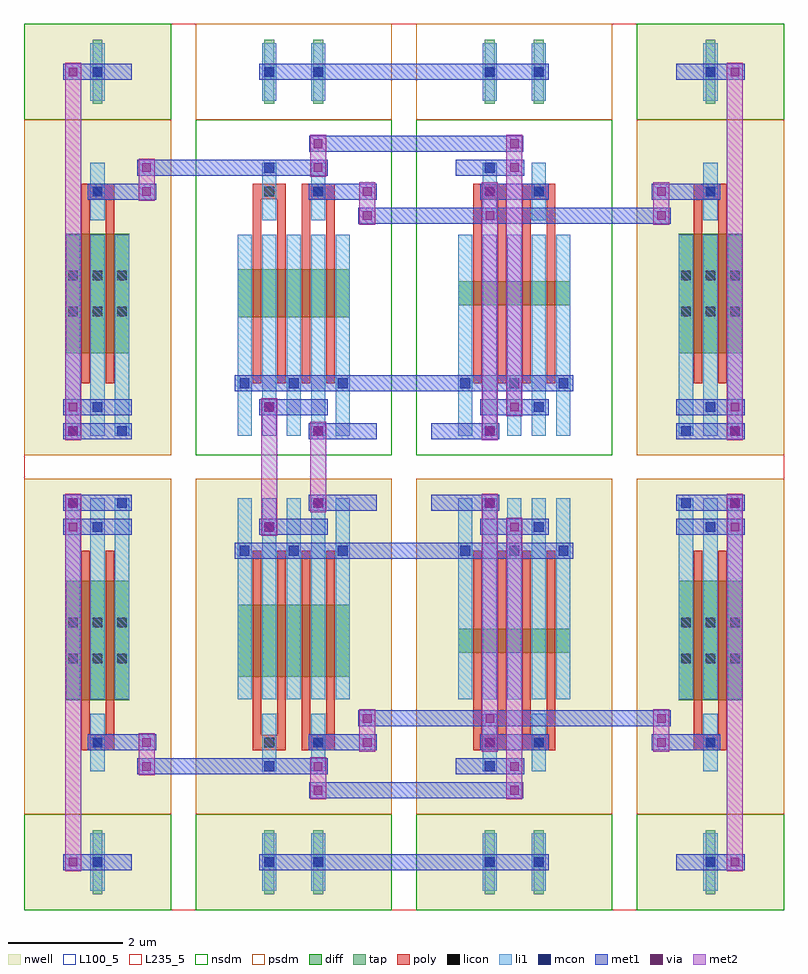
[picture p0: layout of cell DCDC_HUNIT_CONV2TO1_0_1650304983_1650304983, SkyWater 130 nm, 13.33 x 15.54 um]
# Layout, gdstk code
from math import pi, radians
import gdstk
lib = gdstk.Library(unit=1e-6, precision=1e-09)
def R(c, l, rs):  # rectangles x0, y0, x1, y1
    for r in rs: c.add(gdstk.rectangle(r[:2], r[2:], *l))
def A(c, l, x, y, w, h, nx, ny, dx, dy):  # array of equal rectangles
    R(c, l, [(x+i*dx, y+j*dy, x+i*dx+w, y+j*dy+h) for i in range(nx) for j in range(ny)])
def P(c, l, *ps):  # polygons
    for p in ps: c.add(gdstk.Polygon(p, *l))
nwell = (64, 20)
diff = (65, 20)
tap = (65, 44)
poly = (66, 20)
licon = (66, 44)
li1 = (67, 20)
mcon = (67, 44)
met1 = (68, 20)
via = (68, 44)
met2 = (69, 20)
nsdm = (93, 44)
psdm = (94, 20)
L100_5 = (100, 5)
L235_5 = (235, 5)

ccp_pmos_b_88242555_x1_y = lib.new_cell('CCP_PMOS_B_88242555_X1_Y1_1650304983_1650304984_1650304983_1650304983')
R(ccp_pmos_b_88242555_x1_y, nwell, [(0,0,3.44,7.56)])
R(ccp_pmos_b_88242555_x1_y, diff, [(0.735,2.625,2.705,3.045)])
R(ccp_pmos_b_88242555_x1_y, tap, [(1.205,6.16,1.375,7.28), (2.065,6.16,2.235,7.28)])
A(ccp_pmos_b_88242555_x1_y, poly, 1, 1.26, 0.15, 3.36, 4, 1, 0.43, 0)
R(ccp_pmos_b_88242555_x1_y, poly, [(1,4.485,1.58,4.755), (1.86,4.485,2.44,4.755)])
R(ccp_pmos_b_88242555_x1_y, licon, [(1.205,4.535,1.375,4.705), (2.065,4.535,2.235,4.705), (1.205,6.635,1.375,6.805), (2.065,6.635,2.235,6.805)])
A(ccp_pmos_b_88242555_x1_y, li1, 0.735, 0.335, 0.25, 3.53, 5, 1, 0.43, 0)
R(ccp_pmos_b_88242555_x1_y, li1, [(1.165,4.115,1.415,5.125), (2.025,4.115,2.275,5.125), (1.165,6.215,1.415,7.225), (2.025,6.215,2.275,7.225)])
A(ccp_pmos_b_88242555_x1_y, mcon, 0.775, 1.175, 0.17, 0.17, 3, 1, 0.86, 0)
R(ccp_pmos_b_88242555_x1_y, mcon, [(1.205,0.335,1.375,0.505), (2.065,0.755,2.235,0.925), (2.065,4.535,2.235,4.705), (1.205,4.955,1.375,5.125), (1.205,6.635,1.375,6.805), (2.065,6.635,2.235,6.805)])
R(ccp_pmos_b_88242555_x1_y, met1, [(0.26,0.28,1.46,0.56), (1.12,0.7,2.32,0.98), (0.69,1.12,2.75,1.4), (1.12,4.48,2.32,4.76), (0.69,4.9,1.89,5.18), (1.12,6.58,2.32,6.86)])
R(ccp_pmos_b_88242555_x1_y, via, [(1.215,0.345,1.365,0.495), (1.645,0.765,1.795,0.915), (1.215,4.545,1.365,4.695), (1.645,4.965,1.795,5.115)])
R(ccp_pmos_b_88242555_x1_y, met2, [(1.15,0.26,1.43,4.78), (1.58,0.68,1.86,5.2)])
R(ccp_pmos_b_88242555_x1_y, nsdm, [(0,5.88,3.44,7.56)])
R(ccp_pmos_b_88242555_x1_y, psdm, [(0,0,3.44,5.88)])
R(ccp_pmos_b_88242555_x1_y, L100_5, [(0,0,3.44,7.56)])

dp_pmos_b_25364157_x1_y1 = lib.new_cell('DP_PMOS_B_25364157_X1_Y1_1650304985_1650304984_1650304983_1650304983')
R(dp_pmos_b_25364157_x1_y1, nwell, [(0,0,3.44,7.56)])
R(dp_pmos_b_25364157_x1_y1, diff, [(0.735,2.205,2.705,3.465)])
R(dp_pmos_b_25364157_x1_y1, tap, [(1.205,6.16,1.375,7.28), (2.065,6.16,2.235,7.28)])
A(dp_pmos_b_25364157_x1_y1, poly, 1, 1.26, 0.15, 3.36, 4, 1, 0.43, 0)
R(dp_pmos_b_25364157_x1_y1, poly, [(1,4.485,1.58,4.755), (1.86,4.485,2.44,4.755)])
R(dp_pmos_b_25364157_x1_y1, licon, [(1.205,4.535,1.375,4.705), (2.065,4.535,2.235,4.705), (1.205,6.635,1.375,6.805), (2.065,6.635,2.235,6.805)])
A(dp_pmos_b_25364157_x1_y1, li1, 0.735, 0.335, 0.25, 3.53, 5, 1, 0.43, 0)
R(dp_pmos_b_25364157_x1_y1, li1, [(1.165,4.115,1.415,5.125), (2.025,4.115,2.275,5.125), (1.165,6.215,1.415,7.225), (2.025,6.215,2.275,7.225)])
A(dp_pmos_b_25364157_x1_y1, mcon, 0.775, 1.175, 0.17, 0.17, 3, 1, 0.86, 0)
R(dp_pmos_b_25364157_x1_y1, mcon, [(1.205,0.335,1.375,0.505), (2.065,0.755,2.235,0.925), (1.205,4.535,1.375,4.705), (2.065,4.955,2.235,5.125), (1.205,6.635,1.375,6.805), (2.065,6.635,2.235,6.805)])
R(dp_pmos_b_25364157_x1_y1, met1, [(0.26,0.28,1.46,0.56), (1.12,0.7,2.32,0.98), (0.69,1.12,2.75,1.4), (0.26,4.48,1.46,4.76), (1.12,4.9,2.32,5.18), (1.12,6.58,2.32,6.86)])
R(dp_pmos_b_25364157_x1_y1, nsdm, [(0,5.88,3.44,7.56)])
R(dp_pmos_b_25364157_x1_y1, psdm, [(0,0,3.44,5.88)])
R(dp_pmos_b_25364157_x1_y1, L100_5, [(0,0,3.44,7.56)])

dcap_pmos_98843368_x1_y1 = lib.new_cell('DCAP_PMOS_98843368_X1_Y1_1650304984_1650304984_1650304983_1650304983')
R(dcap_pmos_98843368_x1_y1, nwell, [(0,0,2.58,7.56)])
R(dcap_pmos_98843368_x1_y1, diff, [(0.735,1.785,1.845,3.885)])
R(dcap_pmos_98843368_x1_y1, tap, [(1.205,6.16,1.375,7.28)])
R(dcap_pmos_98843368_x1_y1, poly, [(1,1.26,1.15,4.62), (1.43,1.26,1.58,4.62), (1,4.485,1.58,4.755)])
A(dcap_pmos_98843368_x1_y1, licon, 0.775, 2.435, 0.17, 0.17, 3, 2, 0.43, 0.63)
R(dcap_pmos_98843368_x1_y1, licon, [(1.205,4.535,1.375,4.705), (1.205,6.635,1.375,6.805)])
A(dcap_pmos_98843368_x1_y1, li1, 0.735, 0.335, 0.25, 3.53, 3, 1, 0.43, 0)
R(dcap_pmos_98843368_x1_y1, li1, [(1.165,4.115,1.415,5.125), (1.165,6.215,1.415,7.225)])
R(dcap_pmos_98843368_x1_y1, mcon, [(0.775,0.335,0.945,0.505), (1.635,0.335,1.805,0.505), (1.205,0.755,1.375,0.925), (1.205,4.535,1.375,4.705), (1.205,6.635,1.375,6.805)])
R(dcap_pmos_98843368_x1_y1, met1, [(0.69,0.28,1.89,0.56), (0.69,0.7,1.89,0.98), (0.26,4.48,1.46,4.76), (0.69,6.58,1.89,6.86)])
R(dcap_pmos_98843368_x1_y1, via, [(1.645,0.345,1.795,0.495), (1.645,0.765,1.795,0.915), (1.645,6.645,1.795,6.795)])
R(dcap_pmos_98843368_x1_y1, met2, [(1.58,0.26,1.86,6.88)])
R(dcap_pmos_98843368_x1_y1, nsdm, [(0,5.88,2.58,7.56)])
R(dcap_pmos_98843368_x1_y1, psdm, [(0,0,2.58,5.88)])
R(dcap_pmos_98843368_x1_y1, L100_5, [(0,0,2.58,7.56)])

dcdc_xsw_pmos_0_16503049 = lib.new_cell('DCDC_XSW_PMOS_0_1650304984_1650304983_1650304983')
R(dcdc_xsw_pmos_0_16503049, met1, [(5.59,1.12,7.74,1.4), (5.86,4.06,6.18,4.34), (5.86,4.06,6.18,4.34), (5.86,4.06,6.18,4.34), (6.02,4.06,8.17,4.34), (8.01,4.06,8.33,4.34), (8.01,4.06,8.33,4.34), (8.01,4.06,8.33,4.34), (8.17,4.06,11.18,4.34), (11.02,4.06,11.34,4.34), (11.02,4.06,11.34,4.34), (1.99,4.48,2.31,4.76), (1.99,4.48,2.31,4.76), (5.86,4.48,6.18,4.76), (5.86,4.48,6.18,4.76), (5.86,4.48,6.18,4.76), (11.02,4.48,11.34,4.76), (11.02,4.48,11.34,4.76), (1.99,4.9,2.31,5.18), (1.99,4.9,2.31,5.18), (2.15,4.9,4.3,5.18), (5,4.9,5.32,5.18), (5,4.9,5.32,5.18), (5,4.9,5.32,5.18), (5,5.32,5.32,5.6), (5,5.32,5.32,5.6), (5,5.32,5.32,5.6), (5.16,5.32,8.6,5.6), (8.44,5.32,8.76,5.6), (8.44,5.32,8.76,5.6), (8.44,5.32,8.76,5.6), (5.16,6.58,8.17,6.86)])
P(dcdc_xsw_pmos_0_16503049, met1, [(0,0),(0,0),(0,0),(0,0)],
  [(0,0),(0,0),(0,0),(0,0)],
  [(0,0),(0,0),(0,0),(0,0)],
  [(0,0),(0,0),(0,0),(0,0)],
  [(0,0),(0,0),(0,0),(0,0)],
  [(0,0),(0,0),(0,0),(0,0)],
  [(0,0),(0,0),(0,0),(0,0)],
  [(0,0),(0,0),(0,0),(0,0)],
  [(0,0),(0,0),(0,0),(0,0)],
  [(0,0),(0,0),(0,0),(0,0)])
R(dcdc_xsw_pmos_0_16503049, via, [(5.945,4.125,6.095,4.275), (5.945,4.125,6.095,4.275), (5.945,4.125,6.095,4.275), (8.095,4.125,8.245,4.275), (8.095,4.125,8.245,4.275), (8.095,4.125,8.245,4.275), (11.105,4.125,11.255,4.275), (11.105,4.125,11.255,4.275), (2.075,4.545,2.225,4.695), (2.075,4.545,2.225,4.695), (5.945,4.545,6.095,4.695), (5.945,4.545,6.095,4.695), (5.945,4.545,6.095,4.695), (11.105,4.545,11.255,4.695), (11.105,4.545,11.255,4.695), (2.075,4.965,2.225,5.115), (2.075,4.965,2.225,5.115), (5.085,4.965,5.235,5.115), (5.085,4.965,5.235,5.115), (5.085,4.965,5.235,5.115), (5.085,5.385,5.235,5.535), (5.085,5.385,5.235,5.535), (5.085,5.385,5.235,5.535), (8.525,5.385,8.675,5.535), (8.525,5.385,8.675,5.535), (8.525,5.385,8.675,5.535)])
R(dcdc_xsw_pmos_0_16503049, met2, [(5.88,4.04,6.16,4.36), (5.88,4.04,6.16,4.36), (5.88,4.04,6.16,4.36), (8.03,4.04,8.31,4.36), (8.03,4.04,8.31,4.36), (8.03,4.04,8.31,4.36), (11.04,4.04,11.32,4.36), (11.04,4.04,11.32,4.36), (5.88,4.2,6.16,4.62), (11.04,4.2,11.32,4.62), (2.01,4.46,2.29,4.78), (2.01,4.46,2.29,4.78), (5.88,4.46,6.16,4.78), (5.88,4.46,6.16,4.78), (5.88,4.46,6.16,4.78), (11.04,4.46,11.32,4.78), (11.04,4.46,11.32,4.78), (2.01,4.62,2.29,5.04), (2.01,4.88,2.29,5.2), (2.01,4.88,2.29,5.2), (5.02,4.88,5.3,5.2), (5.02,4.88,5.3,5.2), (5.02,4.88,5.3,5.2), (5.02,5.04,5.3,5.46), (8.46,5.04,8.74,5.46), (5.02,5.3,5.3,5.62), (5.02,5.3,5.3,5.62), (5.02,5.3,5.3,5.62), (8.46,5.3,8.74,5.62), (8.46,5.3,8.74,5.62), (8.46,5.3,8.74,5.62)])
P(dcdc_xsw_pmos_0_16503049, met2, [(0,0),(0,0),(0,0),(0,0)],
  [(0,0),(0,0),(0,0),(0,0)],
  [(0,0),(0,0),(0,0),(0,0)],
  [(0,0),(0,0),(0,0),(0,0)])
R(dcdc_xsw_pmos_0_16503049, L235_5, [(0,0,13.33,7.56)])
dcdc_xsw_pmos_0_16503049.add(gdstk.Reference(ccp_pmos_b_88242555_x1_y, (6.88,0)))
dcdc_xsw_pmos_0_16503049.add(gdstk.Reference(dp_pmos_b_25364157_x1_y1, (6.45,0), rotation=pi, x_reflection=True))
dcdc_xsw_pmos_0_16503049.add(gdstk.Reference(dcap_pmos_98843368_x1_y1, (10.75,0)))
dcdc_xsw_pmos_0_16503049.add(gdstk.Reference(dcap_pmos_98843368_x1_y1, (2.58,0), rotation=pi, x_reflection=True))

ccp_nmos_b_82699349_x1_y = lib.new_cell('CCP_NMOS_B_82699349_X1_Y1_1650304983_1650304983_1650304983_1650304983')
R(ccp_nmos_b_82699349_x1_y, diff, [(0.735,2.625,2.705,3.045)])
R(ccp_nmos_b_82699349_x1_y, tap, [(1.205,6.16,1.375,7.28), (2.065,6.16,2.235,7.28)])
A(ccp_nmos_b_82699349_x1_y, poly, 1, 1.26, 0.15, 3.36, 4, 1, 0.43, 0)
R(ccp_nmos_b_82699349_x1_y, poly, [(1,4.485,1.58,4.755), (1.86,4.485,2.44,4.755)])
R(ccp_nmos_b_82699349_x1_y, licon, [(1.205,4.535,1.375,4.705), (2.065,4.535,2.235,4.705), (1.205,6.635,1.375,6.805), (2.065,6.635,2.235,6.805)])
A(ccp_nmos_b_82699349_x1_y, li1, 0.735, 0.335, 0.25, 3.53, 5, 1, 0.43, 0)
R(ccp_nmos_b_82699349_x1_y, li1, [(1.165,4.115,1.415,5.125), (2.025,4.115,2.275,5.125), (1.165,6.215,1.415,7.225), (2.025,6.215,2.275,7.225)])
A(ccp_nmos_b_82699349_x1_y, mcon, 0.775, 1.175, 0.17, 0.17, 3, 1, 0.86, 0)
R(ccp_nmos_b_82699349_x1_y, mcon, [(1.205,0.335,1.375,0.505), (2.065,0.755,2.235,0.925), (2.065,4.535,2.235,4.705), (1.205,4.955,1.375,5.125), (1.205,6.635,1.375,6.805), (2.065,6.635,2.235,6.805)])
R(ccp_nmos_b_82699349_x1_y, met1, [(0.26,0.28,1.46,0.56), (1.12,0.7,2.32,0.98), (0.69,1.12,2.75,1.4), (1.12,4.48,2.32,4.76), (0.69,4.9,1.89,5.18), (1.12,6.58,2.32,6.86)])
R(ccp_nmos_b_82699349_x1_y, via, [(1.215,0.345,1.365,0.495), (1.645,0.765,1.795,0.915), (1.215,4.545,1.365,4.695), (1.645,4.965,1.795,5.115)])
R(ccp_nmos_b_82699349_x1_y, met2, [(1.15,0.26,1.43,4.78), (1.58,0.68,1.86,5.2)])
R(ccp_nmos_b_82699349_x1_y, nsdm, [(0,0,3.44,5.88)])
R(ccp_nmos_b_82699349_x1_y, psdm, [(0,5.88,3.44,7.56)])
R(ccp_nmos_b_82699349_x1_y, L100_5, [(0,0,3.44,7.56)])

dp_nmos_b_83449181_x1_y1 = lib.new_cell('DP_NMOS_B_83449181_X1_Y1_1650304985_1650304983_1650304983_1650304983')
R(dp_nmos_b_83449181_x1_y1, diff, [(0.735,2.415,2.705,3.255)])
R(dp_nmos_b_83449181_x1_y1, tap, [(1.205,6.16,1.375,7.28), (2.065,6.16,2.235,7.28)])
A(dp_nmos_b_83449181_x1_y1, poly, 1, 1.26, 0.15, 3.36, 4, 1, 0.43, 0)
R(dp_nmos_b_83449181_x1_y1, poly, [(1,4.485,1.58,4.755), (1.86,4.485,2.44,4.755)])
R(dp_nmos_b_83449181_x1_y1, licon, [(1.205,4.535,1.375,4.705), (2.065,4.535,2.235,4.705), (1.205,6.635,1.375,6.805), (2.065,6.635,2.235,6.805)])
A(dp_nmos_b_83449181_x1_y1, li1, 0.735, 0.335, 0.25, 3.53, 5, 1, 0.43, 0)
R(dp_nmos_b_83449181_x1_y1, li1, [(1.165,4.115,1.415,5.125), (2.025,4.115,2.275,5.125), (1.165,6.215,1.415,7.225), (2.025,6.215,2.275,7.225)])
A(dp_nmos_b_83449181_x1_y1, mcon, 0.775, 1.175, 0.17, 0.17, 3, 1, 0.86, 0)
R(dp_nmos_b_83449181_x1_y1, mcon, [(1.205,0.335,1.375,0.505), (2.065,0.755,2.235,0.925), (1.205,4.535,1.375,4.705), (2.065,4.955,2.235,5.125), (1.205,6.635,1.375,6.805), (2.065,6.635,2.235,6.805)])
R(dp_nmos_b_83449181_x1_y1, met1, [(0.26,0.28,1.46,0.56), (1.12,0.7,2.32,0.98), (0.69,1.12,2.75,1.4), (0.26,4.48,1.46,4.76), (1.12,4.9,2.32,5.18), (1.12,6.58,2.32,6.86)])
R(dp_nmos_b_83449181_x1_y1, nsdm, [(0,0,3.44,5.88)])
R(dp_nmos_b_83449181_x1_y1, psdm, [(0,5.88,3.44,7.56)])
R(dp_nmos_b_83449181_x1_y1, L100_5, [(0,0,3.44,7.56)])

c_dcap_pmos_98843368_x1_y1 = lib.new_cell('DCAP_PMOS_98843368_X1_Y1_1650304984_1650304983_1650304983_1650304983')
R(c_dcap_pmos_98843368_x1_y1, nwell, [(0,0,2.58,7.56)])
R(c_dcap_pmos_98843368_x1_y1, diff, [(0.735,1.785,1.845,3.885)])
R(c_dcap_pmos_98843368_x1_y1, tap, [(1.205,6.16,1.375,7.28)])
R(c_dcap_pmos_98843368_x1_y1, poly, [(1,1.26,1.15,4.62), (1.43,1.26,1.58,4.62), (1,4.485,1.58,4.755)])
A(c_dcap_pmos_98843368_x1_y1, licon, 0.775, 2.435, 0.17, 0.17, 3, 2, 0.43, 0.63)
R(c_dcap_pmos_98843368_x1_y1, licon, [(1.205,4.535,1.375,4.705), (1.205,6.635,1.375,6.805)])
A(c_dcap_pmos_98843368_x1_y1, li1, 0.735, 0.335, 0.25, 3.53, 3, 1, 0.43, 0)
R(c_dcap_pmos_98843368_x1_y1, li1, [(1.165,4.115,1.415,5.125), (1.165,6.215,1.415,7.225)])
R(c_dcap_pmos_98843368_x1_y1, mcon, [(0.775,0.335,0.945,0.505), (1.635,0.335,1.805,0.505), (1.205,0.755,1.375,0.925), (1.205,4.535,1.375,4.705), (1.205,6.635,1.375,6.805)])
R(c_dcap_pmos_98843368_x1_y1, met1, [(0.69,0.28,1.89,0.56), (0.69,0.7,1.89,0.98), (0.26,4.48,1.46,4.76), (0.69,6.58,1.89,6.86)])
R(c_dcap_pmos_98843368_x1_y1, via, [(1.645,0.345,1.795,0.495), (1.645,0.765,1.795,0.915), (1.645,6.645,1.795,6.795)])
R(c_dcap_pmos_98843368_x1_y1, met2, [(1.58,0.26,1.86,6.88)])
R(c_dcap_pmos_98843368_x1_y1, nsdm, [(0,5.88,2.58,7.56)])
R(c_dcap_pmos_98843368_x1_y1, psdm, [(0,0,2.58,5.88)])
R(c_dcap_pmos_98843368_x1_y1, L100_5, [(0,0,2.58,7.56)])

dcdc_xsw_nmos_0_16503049 = lib.new_cell('DCDC_XSW_NMOS_0_1650304983_1650304983_1650304983')
R(dcdc_xsw_nmos_0_16503049, met1, [(5.59,1.12,7.74,1.4), (5.86,4.06,6.18,4.34), (5.86,4.06,6.18,4.34), (5.86,4.06,6.18,4.34), (6.02,4.06,8.17,4.34), (8.01,4.06,8.33,4.34), (8.01,4.06,8.33,4.34), (8.01,4.06,8.33,4.34), (8.17,4.06,11.18,4.34), (11.02,4.06,11.34,4.34), (11.02,4.06,11.34,4.34), (1.99,4.48,2.31,4.76), (1.99,4.48,2.31,4.76), (5.86,4.48,6.18,4.76), (5.86,4.48,6.18,4.76), (5.86,4.48,6.18,4.76), (11.02,4.48,11.34,4.76), (11.02,4.48,11.34,4.76), (1.99,4.9,2.31,5.18), (1.99,4.9,2.31,5.18), (2.15,4.9,4.3,5.18), (5,4.9,5.32,5.18), (5,4.9,5.32,5.18), (5,4.9,5.32,5.18), (5,5.32,5.32,5.6), (5,5.32,5.32,5.6), (5,5.32,5.32,5.6), (5.16,5.32,8.6,5.6), (8.44,5.32,8.76,5.6), (8.44,5.32,8.76,5.6), (8.44,5.32,8.76,5.6), (5.16,6.58,8.17,6.86)])
P(dcdc_xsw_nmos_0_16503049, met1, [(0,0),(0,0),(0,0),(0,0)],
  [(0,0),(0,0),(0,0),(0,0)],
  [(0,0),(0,0),(0,0),(0,0)],
  [(0,0),(0,0),(0,0),(0,0)],
  [(0,0),(0,0),(0,0),(0,0)],
  [(0,0),(0,0),(0,0),(0,0)],
  [(0,0),(0,0),(0,0),(0,0)],
  [(0,0),(0,0),(0,0),(0,0)],
  [(0,0),(0,0),(0,0),(0,0)],
  [(0,0),(0,0),(0,0),(0,0)])
R(dcdc_xsw_nmos_0_16503049, via, [(5.945,4.125,6.095,4.275), (5.945,4.125,6.095,4.275), (5.945,4.125,6.095,4.275), (8.095,4.125,8.245,4.275), (8.095,4.125,8.245,4.275), (8.095,4.125,8.245,4.275), (11.105,4.125,11.255,4.275), (11.105,4.125,11.255,4.275), (2.075,4.545,2.225,4.695), (2.075,4.545,2.225,4.695), (5.945,4.545,6.095,4.695), (5.945,4.545,6.095,4.695), (5.945,4.545,6.095,4.695), (11.105,4.545,11.255,4.695), (11.105,4.545,11.255,4.695), (2.075,4.965,2.225,5.115), (2.075,4.965,2.225,5.115), (5.085,4.965,5.235,5.115), (5.085,4.965,5.235,5.115), (5.085,4.965,5.235,5.115), (5.085,5.385,5.235,5.535), (5.085,5.385,5.235,5.535), (5.085,5.385,5.235,5.535), (8.525,5.385,8.675,5.535), (8.525,5.385,8.675,5.535), (8.525,5.385,8.675,5.535)])
R(dcdc_xsw_nmos_0_16503049, met2, [(5.88,4.04,6.16,4.36), (5.88,4.04,6.16,4.36), (5.88,4.04,6.16,4.36), (8.03,4.04,8.31,4.36), (8.03,4.04,8.31,4.36), (8.03,4.04,8.31,4.36), (11.04,4.04,11.32,4.36), (11.04,4.04,11.32,4.36), (5.88,4.2,6.16,4.62), (11.04,4.2,11.32,4.62), (2.01,4.46,2.29,4.78), (2.01,4.46,2.29,4.78), (5.88,4.46,6.16,4.78), (5.88,4.46,6.16,4.78), (5.88,4.46,6.16,4.78), (11.04,4.46,11.32,4.78), (11.04,4.46,11.32,4.78), (2.01,4.62,2.29,5.04), (2.01,4.88,2.29,5.2), (2.01,4.88,2.29,5.2), (5.02,4.88,5.3,5.2), (5.02,4.88,5.3,5.2), (5.02,4.88,5.3,5.2), (5.02,5.04,5.3,5.46), (8.46,5.04,8.74,5.46), (5.02,5.3,5.3,5.62), (5.02,5.3,5.3,5.62), (5.02,5.3,5.3,5.62), (8.46,5.3,8.74,5.62), (8.46,5.3,8.74,5.62), (8.46,5.3,8.74,5.62)])
P(dcdc_xsw_nmos_0_16503049, met2, [(0,0),(0,0),(0,0),(0,0)],
  [(0,0),(0,0),(0,0),(0,0)],
  [(0,0),(0,0),(0,0),(0,0)],
  [(0,0),(0,0),(0,0),(0,0)])
R(dcdc_xsw_nmos_0_16503049, L235_5, [(0,0,13.33,7.56)])
dcdc_xsw_nmos_0_16503049.add(gdstk.Reference(ccp_nmos_b_82699349_x1_y, (6.88,0)))
dcdc_xsw_nmos_0_16503049.add(gdstk.Reference(dp_nmos_b_83449181_x1_y1, (6.45,0), rotation=pi, x_reflection=True))
dcdc_xsw_nmos_0_16503049.add(gdstk.Reference(c_dcap_pmos_98843368_x1_y1, (10.75,0)))
dcdc_xsw_nmos_0_16503049.add(gdstk.Reference(c_dcap_pmos_98843368_x1_y1, (2.58,0), rotation=pi, x_reflection=True))

dcdc_hunit_conv2to1_0_16 = lib.new_cell('DCDC_HUNIT_CONV2TO1_0_1650304983_1650304983')
R(dcdc_hunit_conv2to1_0_16, met1, [(4.14,6.58,4.46,6.86), (4.14,6.58,4.46,6.86), (5,7,5.32,7.28), (5,7,5.32,7.28), (5,8.26,5.32,8.54), (5,8.26,5.32,8.54), (4.14,8.68,4.46,8.96), (4.14,8.68,4.46,8.96)])
P(dcdc_hunit_conv2to1_0_16, met1, [(0,0),(0,0),(0,0),(0,0)],
  [(0,0),(0,0),(0,0),(0,0)],
  [(0,0),(0,0),(0,0),(0,0)],
  [(0,0),(0,0),(0,0),(0,0)],
  [(0,0),(0,0),(0,0),(0,0)],
  [(0,0),(0,0),(0,0),(0,0)],
  [(0,0),(0,0),(0,0),(0,0)],
  [(0,0),(0,0),(0,0),(0,0)],
  [(0,0),(0,0),(0,0),(0,0)],
  [(0,0),(0,0),(0,0),(0,0)],
  [(0,0),(0,0),(0,0),(0,0)],
  [(0,0),(0,0),(0,0),(0,0)],
  [(0,0),(0,0),(0,0),(0,0)],
  [(0,0),(0,0),(0,0),(0,0)],
  [(0,0),(0,0),(0,0),(0,0)],
  [(0,0),(0,0),(0,0),(0,0)])
R(dcdc_hunit_conv2to1_0_16, via, [(4.225,6.645,4.375,6.795), (4.225,6.645,4.375,6.795), (5.085,7.065,5.235,7.215), (5.085,7.065,5.235,7.215), (5.085,8.325,5.235,8.475), (5.085,8.325,5.235,8.475), (4.225,8.745,4.375,8.895), (4.225,8.745,4.375,8.895)])
R(dcdc_hunit_conv2to1_0_16, met2, [(4.16,6.56,4.44,6.88), (4.16,6.56,4.44,6.88), (4.16,6.72,4.44,8.82), (5.02,6.98,5.3,7.3), (5.02,6.98,5.3,7.3), (5.02,7.14,5.3,8.4), (5.02,8.24,5.3,8.56), (5.02,8.24,5.3,8.56), (4.16,8.66,4.44,8.98), (4.16,8.66,4.44,8.98)])
P(dcdc_hunit_conv2to1_0_16, met2, [(0,0),(0,0),(0,0),(0,0)],
  [(0,0),(0,0),(0,0),(0,0)],
  [(0,0),(0,0),(0,0),(0,0)],
  [(0,0),(0,0),(0,0),(0,0)])
R(dcdc_hunit_conv2to1_0_16, L235_5, [(0,0,13.33,15.54)])
dcdc_hunit_conv2to1_0_16.add(gdstk.Reference(dcdc_xsw_pmos_0_16503049, (0,7.56), x_reflection=True))
dcdc_hunit_conv2to1_0_16.add(gdstk.Reference(dcdc_xsw_nmos_0_16503049, (0,7.98)))

lib.write_gds('DCDC_HUNIT_CONV2TO1_0_1650304983_1650304983.gds')
